One B-rep face of a CAD part: STEP entity #862.
In plain terms, the planar face has unit normal (0, -0.669, -0.743).
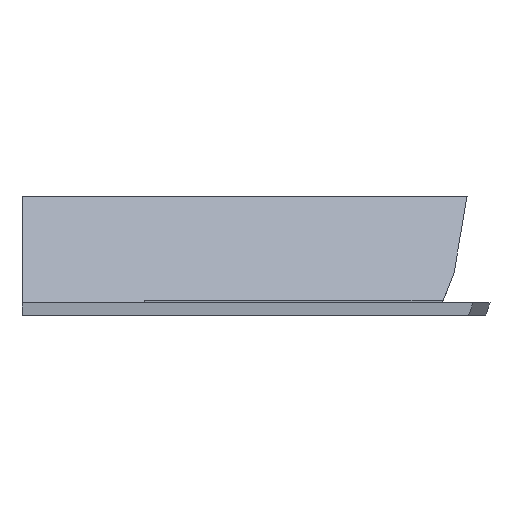
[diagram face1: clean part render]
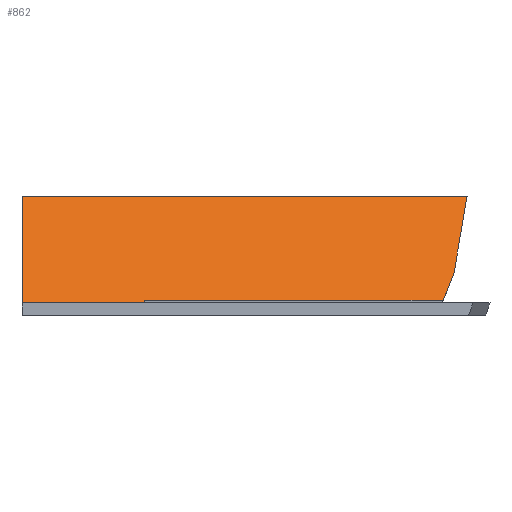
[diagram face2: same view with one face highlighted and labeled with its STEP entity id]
Its self-contained STEP definition (entity closure, numbers rounded to 3 decimals):
#62 = PLANE('',#63);
#63 = AXIS2_PLACEMENT_3D('',#64,#65,#66);
#64 = CARTESIAN_POINT('',(8.796,92.,83.847));
#65 = DIRECTION('',(-0.,-1.,-0.));
#66 = DIRECTION('',(0.,0.,-1.));
#90 = PLANE('',#91);
#91 = AXIS2_PLACEMENT_3D('',#92,#93,#94);
#92 = CARTESIAN_POINT('',(-39.,92.,114.));
#93 = DIRECTION('',(-1.,0.,0.));
#94 = DIRECTION('',(0.,0.,-1.));
#156 = EDGE_CURVE('',#157,#159,#161,.T.);
#157 = VERTEX_POINT('',#158);
#158 = CARTESIAN_POINT('',(-39.,92.,110.6));
#159 = VERTEX_POINT('',#160);
#160 = CARTESIAN_POINT('',(-16.,92.,110.6));
#161 = SURFACE_CURVE('',#162,(#166,#173),.PCURVE_S1.);
#162 = LINE('',#163,#164);
#163 = CARTESIAN_POINT('',(-39.,92.,110.6));
#164 = VECTOR('',#165,1.);
#165 = DIRECTION('',(1.,0.,0.));
#166 = PCURVE('',#62,#167);
#167 = DEFINITIONAL_REPRESENTATION('',(#168),#172);
#168 = LINE('',#169,#170);
#169 = CARTESIAN_POINT('',(-26.753,-47.796));
#170 = VECTOR('',#171,1.);
#171 = DIRECTION('',(0.,1.));
#172 = ( GEOMETRIC_REPRESENTATION_CONTEXT(2) 
PARAMETRIC_REPRESENTATION_CONTEXT() REPRESENTATION_CONTEXT('2D SPACE',''
  ) );
#173 = PCURVE('',#174,#179);
#174 = PLANE('',#175);
#175 = AXIS2_PLACEMENT_3D('',#176,#177,#178);
#176 = CARTESIAN_POINT('',(2.791,81.638,
    119.926));
#177 = DIRECTION('',(-0.,-0.669,-0.743));
#178 = DIRECTION('',(0.,-0.743,0.669));
#179 = DEFINITIONAL_REPRESENTATION('',(#180),#184);
#180 = LINE('',#181,#182);
#181 = CARTESIAN_POINT('',(-13.941,41.791));
#182 = VECTOR('',#183,1.);
#183 = DIRECTION('',(0.,-1.));
#184 = ( GEOMETRIC_REPRESENTATION_CONTEXT(2) 
PARAMETRIC_REPRESENTATION_CONTEXT() REPRESENTATION_CONTEXT('2D SPACE',''
  ) );
#318 = PLANE('',#319);
#319 = AXIS2_PLACEMENT_3D('',#320,#321,#322);
#320 = CARTESIAN_POINT('',(-16.,72.,72.));
#321 = DIRECTION('',(1.,0.,-0.));
#322 = DIRECTION('',(0.,0.,1.));
#633 = PLANE('',#634);
#634 = AXIS2_PLACEMENT_3D('',#635,#636,#637);
#635 = CARTESIAN_POINT('',(-16.,72.,111.));
#636 = DIRECTION('',(0.,0.,1.));
#637 = DIRECTION('',(1.,0.,-0.));
#786 = EDGE_CURVE('',#787,#157,#789,.T.);
#787 = VERTEX_POINT('',#788);
#788 = CARTESIAN_POINT('',(-39.,72.,128.6));
#789 = SURFACE_CURVE('',#790,(#794,#801),.PCURVE_S1.);
#790 = LINE('',#791,#792);
#791 = CARTESIAN_POINT('',(-39.,72.,128.6));
#792 = VECTOR('',#793,1.);
#793 = DIRECTION('',(0.,0.743,-0.669));
#794 = PCURVE('',#90,#795);
#795 = DEFINITIONAL_REPRESENTATION('',(#796),#800);
#796 = LINE('',#797,#798);
#797 = CARTESIAN_POINT('',(-14.6,20.));
#798 = VECTOR('',#799,1.);
#799 = DIRECTION('',(0.669,-0.743));
#800 = ( GEOMETRIC_REPRESENTATION_CONTEXT(2) 
PARAMETRIC_REPRESENTATION_CONTEXT() REPRESENTATION_CONTEXT('2D SPACE',''
  ) );
#801 = PCURVE('',#174,#802);
#802 = DEFINITIONAL_REPRESENTATION('',(#803),#807);
#803 = LINE('',#804,#805);
#804 = CARTESIAN_POINT('',(12.967,41.791));
#805 = VECTOR('',#806,1.);
#806 = DIRECTION('',(-1.,0.));
#807 = ( GEOMETRIC_REPRESENTATION_CONTEXT(2) 
PARAMETRIC_REPRESENTATION_CONTEXT() REPRESENTATION_CONTEXT('2D SPACE',''
  ) );
#825 = PLANE('',#826);
#826 = AXIS2_PLACEMENT_3D('',#827,#828,#829);
#827 = CARTESIAN_POINT('',(48.,72.,132.));
#828 = DIRECTION('',(0.,1.,0.));
#829 = DIRECTION('',(-1.,0.,0.));
#862 = ADVANCED_FACE('',(#863),#174,.T.);
#863 = FACE_BOUND('',#864,.T.);
#864 = EDGE_LOOP('',(#865,#888,#889,#890,#911,#932,#960));
#865 = ORIENTED_EDGE('',*,*,#866,.T.);
#866 = EDGE_CURVE('',#867,#787,#869,.T.);
#867 = VERTEX_POINT('',#868);
#868 = CARTESIAN_POINT('',(44.68,72.,128.6));
#869 = SURFACE_CURVE('',#870,(#874,#881),.PCURVE_S1.);
#870 = LINE('',#871,#872);
#871 = CARTESIAN_POINT('',(48.,72.,128.6));
#872 = VECTOR('',#873,1.);
#873 = DIRECTION('',(-1.,0.,0.));
#874 = PCURVE('',#174,#875);
#875 = DEFINITIONAL_REPRESENTATION('',(#876),#880);
#876 = LINE('',#877,#878);
#877 = CARTESIAN_POINT('',(12.967,-45.209));
#878 = VECTOR('',#879,1.);
#879 = DIRECTION('',(0.,1.));
#880 = ( GEOMETRIC_REPRESENTATION_CONTEXT(2) 
PARAMETRIC_REPRESENTATION_CONTEXT() REPRESENTATION_CONTEXT('2D SPACE',''
  ) );
#881 = PCURVE('',#825,#882);
#882 = DEFINITIONAL_REPRESENTATION('',(#883),#887);
#883 = LINE('',#884,#885);
#884 = CARTESIAN_POINT('',(0.,-3.4));
#885 = VECTOR('',#886,1.);
#886 = DIRECTION('',(1.,0.));
#887 = ( GEOMETRIC_REPRESENTATION_CONTEXT(2) 
PARAMETRIC_REPRESENTATION_CONTEXT() REPRESENTATION_CONTEXT('2D SPACE',''
  ) );
#888 = ORIENTED_EDGE('',*,*,#786,.T.);
#889 = ORIENTED_EDGE('',*,*,#156,.T.);
#890 = ORIENTED_EDGE('',*,*,#891,.T.);
#891 = EDGE_CURVE('',#159,#892,#894,.T.);
#892 = VERTEX_POINT('',#893);
#893 = CARTESIAN_POINT('',(-16.,91.556,111.));
#894 = SURFACE_CURVE('',#895,(#899,#905),.PCURVE_S1.);
#895 = LINE('',#896,#897);
#896 = CARTESIAN_POINT('',(-16.,90.891,111.598));
#897 = VECTOR('',#898,1.);
#898 = DIRECTION('',(0.,-0.743,0.669));
#899 = PCURVE('',#174,#900);
#900 = DEFINITIONAL_REPRESENTATION('',(#901),#904);
#901 = B_SPLINE_CURVE_WITH_KNOTS('',1,(#902,#903),.UNSPECIFIED.,.F.,.F.,
  (2,2),(-1.492,-0.894),.PIECEWISE_BEZIER_KNOTS.);
#902 = CARTESIAN_POINT('',(-13.941,18.791));
#903 = CARTESIAN_POINT('',(-13.343,18.791));
#904 = ( GEOMETRIC_REPRESENTATION_CONTEXT(2) 
PARAMETRIC_REPRESENTATION_CONTEXT() REPRESENTATION_CONTEXT('2D SPACE',''
  ) );
#905 = PCURVE('',#318,#906);
#906 = DEFINITIONAL_REPRESENTATION('',(#907),#910);
#907 = B_SPLINE_CURVE_WITH_KNOTS('',1,(#908,#909),.UNSPECIFIED.,.F.,.F.,
  (2,2),(-1.492,-0.894),.PIECEWISE_BEZIER_KNOTS.);
#908 = CARTESIAN_POINT('',(38.6,-20.));
#909 = CARTESIAN_POINT('',(39.,-19.556));
#910 = ( GEOMETRIC_REPRESENTATION_CONTEXT(2) 
PARAMETRIC_REPRESENTATION_CONTEXT() REPRESENTATION_CONTEXT('2D SPACE',''
  ) );
#911 = ORIENTED_EDGE('',*,*,#912,.F.);
#912 = EDGE_CURVE('',#913,#892,#915,.T.);
#913 = VERTEX_POINT('',#914);
#914 = CARTESIAN_POINT('',(40.178,91.556,111.));
#915 = SURFACE_CURVE('',#916,(#920,#926),.PCURVE_S1.);
#916 = LINE('',#917,#918);
#917 = CARTESIAN_POINT('',(-6.604,91.556,111.));
#918 = VECTOR('',#919,1.);
#919 = DIRECTION('',(-1.,0.,0.));
#920 = PCURVE('',#174,#921);
#921 = DEFINITIONAL_REPRESENTATION('',(#922),#925);
#922 = B_SPLINE_CURVE_WITH_KNOTS('',1,(#923,#924),.UNSPECIFIED.,.F.,.F.,
  (2,2),(-51.284,9.396),.PIECEWISE_BEZIER_KNOTS.);
#923 = CARTESIAN_POINT('',(-13.343,-41.889));
#924 = CARTESIAN_POINT('',(-13.343,18.791));
#925 = ( GEOMETRIC_REPRESENTATION_CONTEXT(2) 
PARAMETRIC_REPRESENTATION_CONTEXT() REPRESENTATION_CONTEXT('2D SPACE',''
  ) );
#926 = PCURVE('',#633,#927);
#927 = DEFINITIONAL_REPRESENTATION('',(#928),#931);
#928 = B_SPLINE_CURVE_WITH_KNOTS('',1,(#929,#930),.UNSPECIFIED.,.F.,.F.,
  (2,2),(-51.284,9.396),.PIECEWISE_BEZIER_KNOTS.);
#929 = CARTESIAN_POINT('',(60.68,19.556));
#930 = CARTESIAN_POINT('',(0.,19.556));
#931 = ( GEOMETRIC_REPRESENTATION_CONTEXT(2) 
PARAMETRIC_REPRESENTATION_CONTEXT() REPRESENTATION_CONTEXT('2D SPACE',''
  ) );
#932 = ORIENTED_EDGE('',*,*,#933,.T.);
#933 = EDGE_CURVE('',#913,#934,#936,.T.);
#934 = VERTEX_POINT('',#935);
#935 = CARTESIAN_POINT('',(42.226,86.435,
    115.609));
#936 = SURFACE_CURVE('',#937,(#941,#948),.PCURVE_S1.);
#937 = LINE('',#938,#939);
#938 = CARTESIAN_POINT('',(40.,92.,110.6));
#939 = VECTOR('',#940,1.);
#940 = DIRECTION('',(0.285,-0.712,0.641));
#941 = PCURVE('',#174,#942);
#942 = DEFINITIONAL_REPRESENTATION('',(#943),#947);
#943 = LINE('',#944,#945);
#944 = CARTESIAN_POINT('',(-13.941,-37.209));
#945 = VECTOR('',#946,1.);
#946 = DIRECTION('',(0.959,-0.285));
#947 = ( GEOMETRIC_REPRESENTATION_CONTEXT(2) 
PARAMETRIC_REPRESENTATION_CONTEXT() REPRESENTATION_CONTEXT('2D SPACE',''
  ) );
#948 = PCURVE('',#949,#954);
#949 = PLANE('',#950);
#950 = AXIS2_PLACEMENT_3D('',#951,#952,#953);
#951 = CARTESIAN_POINT('',(40.,92.,114.));
#952 = DIRECTION('',(-0.928,-0.371,-0.));
#953 = DIRECTION('',(0.285,-0.712,0.641));
#954 = DEFINITIONAL_REPRESENTATION('',(#955),#959);
#955 = LINE('',#956,#957);
#956 = CARTESIAN_POINT('',(-2.18,-2.609));
#957 = VECTOR('',#958,1.);
#958 = DIRECTION('',(1.,0.));
#959 = ( GEOMETRIC_REPRESENTATION_CONTEXT(2) 
PARAMETRIC_REPRESENTATION_CONTEXT() REPRESENTATION_CONTEXT('2D SPACE',''
  ) );
#960 = ORIENTED_EDGE('',*,*,#961,.F.);
#961 = EDGE_CURVE('',#867,#934,#962,.T.);
#962 = SURFACE_CURVE('',#963,(#966,#972),.PCURVE_S1.);
#963 = B_SPLINE_CURVE_WITH_KNOTS('',1,(#964,#965),.UNSPECIFIED.,.F.,.F.,
  (2,2),(0.,1.),.PIECEWISE_BEZIER_KNOTS.);
#964 = CARTESIAN_POINT('',(44.68,72.,128.6));
#965 = CARTESIAN_POINT('',(41.28,92.,110.6));
#966 = PCURVE('',#174,#967);
#967 = DEFINITIONAL_REPRESENTATION('',(#968),#971);
#968 = B_SPLINE_CURVE_WITH_KNOTS('',1,(#969,#970),.UNSPECIFIED.,.F.,.F.,
  (2,2),(0.,1.),.PIECEWISE_BEZIER_KNOTS.);
#969 = CARTESIAN_POINT('',(12.967,-41.889));
#970 = CARTESIAN_POINT('',(-13.941,-38.489));
#971 = ( GEOMETRIC_REPRESENTATION_CONTEXT(2) 
PARAMETRIC_REPRESENTATION_CONTEXT() REPRESENTATION_CONTEXT('2D SPACE',''
  ) );
#972 = PCURVE('',#973,#978);
#973 = B_SPLINE_SURFACE_WITH_KNOTS('',1,1,(
    (#974,#975)
    ,(#976,#977
    )),.UNSPECIFIED.,.F.,.F.,.F.,(2,2),(2,2),(0.,130.535),(0.,1.
    ),.PIECEWISE_BEZIER_KNOTS.);
#974 = CARTESIAN_POINT('',(81.2,0.,72.));
#975 = CARTESIAN_POINT('',(11.2,200.,72.));
#976 = CARTESIAN_POINT('',(55.6,0.,200.));
#977 = CARTESIAN_POINT('',(-14.4,200.,200.));
#978 = DEFINITIONAL_REPRESENTATION('',(#979),#982);
#979 = B_SPLINE_CURVE_WITH_KNOTS('',1,(#980,#981),.UNSPECIFIED.,.F.,.F.,
  (2,2),(0.,1.),.PIECEWISE_BEZIER_KNOTS.);
#980 = CARTESIAN_POINT('',(57.721,0.36));
#981 = CARTESIAN_POINT('',(39.364,0.46));
#982 = ( GEOMETRIC_REPRESENTATION_CONTEXT(2) 
PARAMETRIC_REPRESENTATION_CONTEXT() REPRESENTATION_CONTEXT('2D SPACE',''
  ) );
